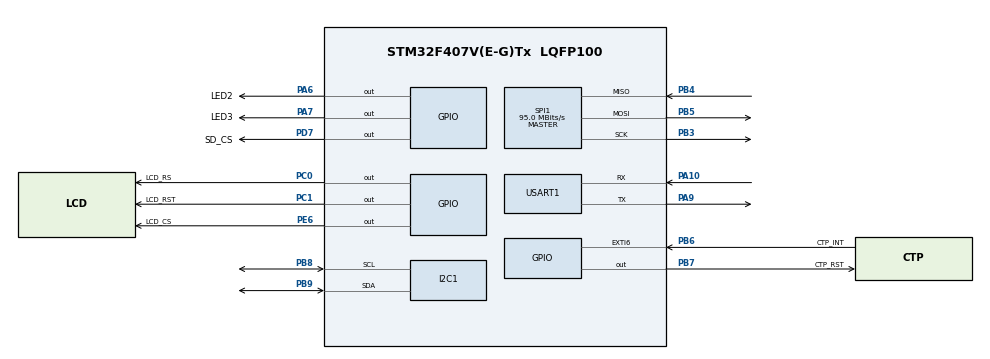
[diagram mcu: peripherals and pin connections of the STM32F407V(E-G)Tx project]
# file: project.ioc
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Dma.Request0=USART1_TX
Dma.Request1=SPI1_TX
Dma.Request2=SPI1_RX
Dma.SPI1_RX.2.Direction=DMA_PERIPH_TO_MEMORY
Dma.SPI1_RX.2.FIFOMode=DMA_FIFOMODE_DISABLE
Dma.SPI1_RX.2.Instance=DMA2_Stream0
Dma.SPI1_RX.2.MemDataAlignment=DMA_MDATAALIGN_BYTE
Dma.SPI1_RX.2.MemInc=DMA_MINC_ENABLE
Dma.SPI1_RX.2.Mode=DMA_NORMAL
Dma.SPI1_RX.2.PeriphDataAlignment=DMA_PDATAALIGN_BYTE
Dma.SPI1_RX.2.PeriphInc=DMA_PINC_DISABLE
Dma.SPI1_RX.2.Priority=DMA_PRIORITY_MEDIUM
Dma.SPI1_TX.1.Direction=DMA_MEMORY_TO_PERIPH
Dma.SPI1_TX.1.FIFOMode=DMA_FIFOMODE_DISABLE
Dma.SPI1_TX.1.Instance=DMA2_Stream3
Dma.SPI1_TX.1.MemDataAlignment=DMA_MDATAALIGN_BYTE
Dma.SPI1_TX.1.MemInc=DMA_MINC_ENABLE
Dma.SPI1_TX.1.Mode=DMA_NORMAL
Dma.SPI1_TX.1.PeriphDataAlignment=DMA_PDATAALIGN_BYTE
Dma.SPI1_TX.1.PeriphInc=DMA_PINC_DISABLE
Dma.SPI1_TX.1.Priority=DMA_PRIORITY_MEDIUM
Dma.USART1_TX.0.Direction=DMA_MEMORY_TO_PERIPH
Dma.USART1_TX.0.FIFOMode=DMA_FIFOMODE_DISABLE
Dma.USART1_TX.0.Instance=DMA2_Stream7
Dma.USART1_TX.0.MemDataAlignment=DMA_MDATAALIGN_BYTE
Dma.USART1_TX.0.MemInc=DMA_MINC_ENABLE
Dma.USART1_TX.0.Mode=DMA_NORMAL
Dma.USART1_TX.0.PeriphDataAlignment=DMA_PDATAALIGN_BYTE
Dma.USART1_TX.0.PeriphInc=DMA_PINC_DISABLE
Dma.USART1_TX.0.Priority=DMA_PRIORITY_MEDIUM
FREERTOS.Tasks01=defaultTask,0,128,StartDefaultTask,Default,NULL,Dynamic,NULL,NULL;BlinkLED2,-1,128,BlinkLED2_Task,Default,NULL,Dynamic,NULL,NULL;LVGL_TaskHandle,0,2304,LVGL_TaskHandler_Task,Default,NULL,Dynamic,NULL,NULL;FT6336_ScanTask,1,128,FT6336_Scan_Task,Default,NULL,Dynamic,NULL,NULL
FREERTOS.configENABLE_FPU=1
FREERTOS.configUSE_NEWLIB_REENTRANT=0
I2C1.I2C_Mode=I2C_Fast
Mcu.Family=STM32F4
Mcu.Name=STM32F407V(E-G)Tx
Mcu.Package=LQFP100
NVIC.DMA2_Stream0_IRQn=true\:5\:0\:true\:false\:true\:true\:false\:true\:true
NVIC.DMA2_Stream3_IRQn=true\:5\:0\:true\:false\:true\:true\:false\:true\:true
NVIC.DMA2_Stream7_IRQn=true\:5\:0\:true\:false\:true\:true\:false\:true\:true
NVIC.EXTI9_5_IRQn=true\:5\:0\:true\:false\:true\:true\:true\:true\:true
NVIC.PriorityGroup=NVIC_PRIORITYGROUP_4
NVIC.SPI1_IRQn=true\:3\:0\:true\:false\:true\:false\:true\:true\:true
NVIC.TIM1_BRK_TIM9_IRQn=true\:15\:0\:false\:false\:true\:false\:false\:true\:true
NVIC.TIM3_IRQn=true\:5\:0\:true\:false\:true\:true\:true\:true\:true
NVIC.TimeBase=TIM1_BRK_TIM9_IRQn
NVIC.TimeBaseIP=TIM9
NVIC.USART1_IRQn=true\:6\:0\:true\:false\:true\:true\:false\:true\:true
PA10.Mode=Asynchronous
PA10.Signal=USART1_RX
PA13.Mode=Serial_Wire
PA13.Signal=SYS_JTMS-SWDIO
PA14.Mode=Serial_Wire
PA14.Signal=SYS_JTCK-SWCLK
PA6.GPIO_Label=LED2
PA6.GPIO_Speed=GPIO_SPEED_FREQ_HIGH
PA6.PinState=GPIO_PIN_SET
PA6.Signal=GPIO_Output
PA7.GPIO_Label=LED3
PA7.GPIO_Speed=GPIO_SPEED_FREQ_HIGH
PA7.PinState=GPIO_PIN_SET
PA7.Signal=GPIO_Output
PA9.Mode=Asynchronous
PA9.Signal=USART1_TX
PB3.GPIO_PuPd=GPIO_PULLUP
PB3.Mode=Full_Duplex_Master
PB3.Signal=SPI1_SCK
PB4.GPIO_PuPd=GPIO_PULLUP
PB4.Mode=Full_Duplex_Master
PB4.Signal=SPI1_MISO
PB5.GPIO_PuPd=GPIO_PULLUP
PB5.Mode=Full_Duplex_Master
PB5.Signal=SPI1_MOSI
PB6.GPIO_Label=CTP_INT
PB6.GPIO_ModeDefaultEXTI=GPIO_MODE_IT_FALLING
PB6.GPIO_PuPd=GPIO_PULLUP
PB6.Signal=GPXTI6
PB7.GPIO_Label=CTP_RST
PB7.GPIO_Speed=GPIO_SPEED_FREQ_VERY_HIGH
PB7.PinState=GPIO_PIN_SET
PB7.Signal=GPIO_Output
PB8.GPIO_Pu=GPIO_PULLUP
PB8.Mode=I2C
PB8.Signal=I2C1_SCL
PB9.GPIO_Pu=GPIO_PULLUP
PB9.Mode=I2C
PB9.Signal=I2C1_SDA
PC0.GPIO_Label=LCD_RS
PC0.GPIO_ModeDefaultOutputPP=GPIO_MODE_OUTPUT_PP
PC0.GPIO_Speed=GPIO_SPEED_FREQ_VERY_HIGH
PC0.PinState=GPIO_PIN_SET
PC0.Signal=GPIO_Output
PC1.GPIO_Label=LCD_RST
PC1.GPIO_Speed=GPIO_SPEED_FREQ_VERY_HIGH
PC1.PinState=GPIO_PIN_SET
PC1.Signal=GPIO_Output
PC14-OSC32_IN.Mode=LSE-External-Oscillator
PC14-OSC32_IN.Signal=RCC_OSC32_IN
PC15-OSC32_OUT.Mode=LSE-External-Oscillator
PC15-OSC32_OUT.Signal=RCC_OSC32_OUT
PD7.GPIO_Label=SD_CS
PD7.GPIO_ModeDefaultOutputPP=GPIO_MODE_OUTPUT_PP
PD7.GPIO_PuPd=GPIO_PULLUP
PD7.GPIO_Speed=GPIO_SPEED_FREQ_VERY_HIGH
PD7.PinState=GPIO_PIN_SET
PD7.Signal=GPIO_Output
PE6.GPIO_Label=LCD_CS
PE6.GPIO_Speed=GPIO_SPEED_FREQ_VERY_HIGH
PE6.PinState=GPIO_PIN_SET
PE6.Signal=GPIO_Output
PH0-OSC_IN.Mode=HSE-External-Oscillator
PH0-OSC_IN.Signal=RCC_OSC_IN
PH1-OSC_OUT.Mode=HSE-External-Oscillator
PH1-OSC_OUT.Signal=RCC_OSC_OUT
ProjectManager.HeapSize=0x3500
ProjectManager.StackSize=0x1000
ProjectManager.TargetToolchain=MDK-ARM V5.32
RCC.48MHZClocksFreq_Value=95000000
RCC.AHBFreq_Value=190000000
RCC.APB1CLKDivider=RCC_HCLK_DIV4
RCC.APB1Freq_Value=47500000
RCC.APB1TimFreq_Value=95000000
RCC.APB2Freq_Value=190000000
RCC.APB2TimFreq_Value=190000000
RCC.CortexFreq_Value=190000000
RCC.HCLKFreq_Value=190000000
RCC.HSE_VALUE=8000000
RCC.HSI_VALUE=16000000
RCC.PLLM=4
RCC.PLLN=190
RCC.PLLSourceVirtual=RCC_PLLSOURCE_HSE
RCC.SYSCLKFreq_VALUE=190000000
RCC.SYSCLKSource=RCC_SYSCLKSOURCE_PLLCLK
RCC.VCOOutputFreq_Value=380000000
SPI1.BaudRatePrescaler=SPI_BAUDRATEPRESCALER_2
SPI1.CLKPhase=SPI_PHASE_2EDGE
SPI1.CLKPolarity=SPI_POLARITY_HIGH
SPI1.CalculateBaudRate=95.0 MBits/s
SPI1.Direction=SPI_DIRECTION_2LINES
SPI1.Mode=SPI_MODE_MASTER
SPI1.VirtualType=VM_MASTER
TIM3.AutoReloadPreload=TIM_AUTORELOAD_PRELOAD_ENABLE
TIM3.Period=1000-1
TIM3.Prescaler=90-1
USART1.VirtualMode=VM_ASYNC
VP_CRC_VS_CRC.Mode=CRC_Activate
VP_FREERTOS_VS_CMSIS_V1.Mode=CMSIS_V1
VP_SYS_VS_tim9.Mode=TIM9
VP_TIM3_VS_ClockSourceINT.Mode=Internal
board=custom

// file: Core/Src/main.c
/* USER CODE BEGIN Header */
/**
 ******************************************************************************
 * @file    : main.c
 * @brief   : Main program body
 * @author  : Zeruns
 * @brief   : 基于STM32F407的LVGL工程模板（MSP3526屏幕）,FreeRTOS版
 * @version : 0.2
 * @date    : 2024-05-27
 * @作者个人博客  : https://blog.zeruns.tech
 * @B站空间       : https://space.bilibili.com/8320520
 ******************************************************************************
 * @attention
 *
 * Copyright (c) 2024 STMicroelectronics.
 * All rights reserved.
 *
 * This software is licensed under terms that can be found in the LICENSE file
 * in the root directory of this software component.
 * If no LICENSE file comes with this software, it is provided AS-IS.
 *
 ******************************************************************************
 *    硬件接线：
 *    LCD            MCU/开发板         功能描述
 * ----------------------------------------------------------------------------
 *    GND       ->      GND     ->    LCD屏电源地
 *    VCC       ->      5V      ->    LCD屏电源正极
 *    LCD_CS    ->      PE6     ->    LCD屏SPI片选
 *    LCD_RST   ->      PC1     ->    LCD屏复位
 *    LCD_RS    ->      PC0     ->    LCD屏命令/数据选择
 *    SDI(MOSI) ->      PB5     ->    LCD屏SPI数据线，主机输出从机输入
 *    SCK       ->      PB3     ->    LCD屏SPI时钟线
 *    LED       ->      3.3V（可以自己接IO口，用软件控制背光）
 *    SDO(MISO) ->      PB4     ->    LCD屏SPI数据线，主机输入从机输出
 *    CTP_SCL   ->      PB8     ->    电容触摸屏控制器I2C时钟线
 *    CTP_RST   ->      PB7     ->    电容触摸屏控制器复位
 *    CTP_SDA   ->      PB9     ->    电容触摸屏控制器I2C数据线
 *    CTP_INT   ->      PB6     ->    电容触摸屏控制器中断信号
 ******************************************************************************
 */
/* USER CODE END Header */
#include "main.h"
#include "cmsis_os.h"
#include "crc.h"
#include "dma.h"
#include "i2c.h"
#include "spi.h"
#include "tim.h"
#include "usart.h"
#include "gpio.h"

/* USER CODE BEGIN Includes */
#include "LCD.h"
#include "lvgl.h"
#include "lv_port_disp.h"
#include "lv_port_indev.h"
#include "lv_demos.h"
#include "touch.h"
#include "FT6336.h"
/* USER CODE END Includes */

void SystemClock_Config(void);
void MX_FREERTOS_Init(void);

int main(void)
{

  /* MCU Configuration--------------------------------------------------------*/

  /* Reset of all peripherals, Initializes the Flash interface and the Systick. */
  HAL_Init();

  /* Configure the system clock */
  SystemClock_Config();

  /* Initialize all configured peripherals */
  MX_GPIO_Init();
  MX_DMA_Init();
  MX_USART1_UART_Init();
  MX_I2C1_Init();
  MX_TIM3_Init();
  MX_CRC_Init();
  MX_SPI1_Init();
  /* USER CODE BEGIN 2 */
  HAL_TIM_Base_Start_IT(&htim3); // 启动定时器3和定时器中断，1Hz

  /* USER CODE END 2 */

  /* Call init function for freertos objects (in cmsis_os2.c) */
  MX_FREERTOS_Init();

  /* Start scheduler */
  osKernelStart();

  /* We should never get here as control is now taken by the scheduler */

  /* Infinite loop */
  /* USER CODE BEGIN WHILE */

  //while (1)
  //{
    /* USER CODE END WHILE */

    /* USER CODE BEGIN 3 */
  //}
  /* USER CODE END 3 */
}

void SystemClock_Config(void)
{
  RCC_OscInitTypeDef RCC_OscInitStruct = {0};
  RCC_ClkInitTypeDef RCC_ClkInitStruct = {0};

  /** Configure the main internal regulator output voltage
  */
  __HAL_RCC_PWR_CLK_ENABLE();
  __HAL_PWR_VOLTAGESCALING_CONFIG(PWR_REGULATOR_VOLTAGE_SCALE1);

  /** Initializes the RCC Oscillators according to the specified parameters
  * in the RCC_OscInitTypeDef structure.
  */
  RCC_OscInitStruct.OscillatorType = RCC_OSCILLATORTYPE_HSE;
  RCC_OscInitStruct.HSEState = RCC_HSE_ON;
  RCC_OscInitStruct.PLL.PLLState = RCC_PLL_ON;
  RCC_OscInitStruct.PLL.PLLSource = RCC_PLLSOURCE_HSE;
  RCC_OscInitStruct.PLL.PLLM = 4;
  RCC_OscInitStruct.PLL.PLLN = 180;
  RCC_OscInitStruct.PLL.PLLP = RCC_PLLP_DIV2;
  RCC_OscInitStruct.PLL.PLLQ = 4;
  if (HAL_RCC_OscConfig(&RCC_OscInitStruct) != HAL_OK)
  {
    Error_Handler();
  }

  /** Initializes the CPU, AHB and APB buses clocks
  */
  RCC_ClkInitStruct.ClockType = RCC_CLOCKTYPE_HCLK|RCC_CLOCKTYPE_SYSCLK
                              |RCC_CLOCKTYPE_PCLK1|RCC_CLOCKTYPE_PCLK2;
  RCC_ClkInitStruct.SYSCLKSource = RCC_SYSCLKSOURCE_PLLCLK;
  RCC_ClkInitStruct.AHBCLKDivider = RCC_SYSCLK_DIV1;
  RCC_ClkInitStruct.APB1CLKDivider = RCC_HCLK_DIV4;
  RCC_ClkInitStruct.APB2CLKDivider = RCC_HCLK_DIV1;

  if (HAL_RCC_ClockConfig(&RCC_ClkInitStruct, FLASH_LATENCY_5) != HAL_OK)
  {
    Error_Handler();
  }
}

void HAL_TIM_PeriodElapsedCallback(TIM_HandleTypeDef *htim)
{
  if (htim->Instance == TIM9) {
    HAL_IncTick();
  }
  /* USER CODE BEGIN Callback 1 */
	if (htim->Instance == TIM3) // 定时器TIM3，中断时间1ms
  {
    //lv_tick_inc(1); // LVGL时基
  }
  /* USER CODE END Callback 1 */
}

void Error_Handler(void)
{
  __disable_irq();
  while (1)
  {
  }
}

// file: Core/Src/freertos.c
/* USER CODE BEGIN Header */
/**
 ******************************************************************************
 * File Name          : freertos.c
 * Description        : Code for freertos applications
 * @author  : Zeruns
 * @brief   : 基于STM32F407的LVGL工程模板（MSP3526屏幕）,FreeRTOS版
 * @version : 0.2
 * @date    : 2024-05-27
 * @作者个人博客  : https://blog.zeruns.tech
 * @B站空间       : https://space.bilibili.com/8320520
 ******************************************************************************
 * @attention
 *
 * Copyright (c) 2024 STMicroelectronics.
 * All rights reserved.
 *
 * This software is licensed under terms that can be found in the LICENSE file
 * in the root directory of this software component.
 * If no LICENSE file comes with this software, it is provided AS-IS.
 *
 ******************************************************************************
 *    硬件接线：
 *    LCD            MCU/开发板         功能描述
 * ----------------------------------------------------------------------------
 *    GND       ->      GND     ->    LCD屏电源地
 *    VCC       ->      5V      ->    LCD屏电源正极
 *    LCD_CS    ->      PE6     ->    LCD屏SPI片选
 *    LCD_RST   ->      PC1     ->    LCD屏复位
 *    LCD_RS    ->      PC0     ->    LCD屏命令/数据选择
 *    SDI(MOSI) ->      PB5     ->    LCD屏SPI数据线，主机输出从机输入
 *    SCK       ->      PB3     ->    LCD屏SPI时钟线
 *    LED       ->      3.3V（可以自己接IO口，用软件控制背光）
 *    SDO(MISO) ->      PB4     ->    LCD屏SPI数据线，主机输入从机输出
 *    CTP_SCL   ->      PB8     ->    电容触摸屏控制器I2C时钟线
 *    CTP_RST   ->      PB7     ->    电容触摸屏控制器复位
 *    CTP_SDA   ->      PB9     ->    电容触摸屏控制器I2C数据线
 *    CTP_INT   ->      PB6     ->    电容触摸屏控制器中断信号
 ******************************************************************************
 */
/* USER CODE END Header */

#include "FreeRTOS.h"
#include "task.h"
#include "main.h"
#include "cmsis_os.h"

/* USER CODE BEGIN Includes */
#include "usart.h"
#include "gpio.h"
#include "LCD.h"
#include "touch.h"
#include "lvgl.h"
#include "lv_port_disp.h"
#include "lv_port_indev.h"
#include "lv_demos.h"
/* USER CODE END Includes */

/* USER CODE BEGIN Variables */
osSemaphoreId SPI1_Send_OK; // 定义信号量，用于SPI1发送完成标志
uint8_t CTP_INT_Flag;       // 触摸屏中断标志位
/* USER CODE END Variables */
osThreadId defaultTaskHandle;
osThreadId BlinkLED2Handle;
osThreadId LVGL_TaskHandleHandle;
osThreadId FT6336_ScanTaskHandle;

void StartDefaultTask(void const *argument);
void BlinkLED2_Task(void const *argument);
void LVGL_TaskHandler_Task(void const *argument);
void FT6336_Scan_Task(void const *argument);

void MX_FREERTOS_Init(void); /* (MISRA C 2004 rule 8.1) */

/* GetIdleTaskMemory prototype (linked to static allocation support) */
void vApplicationGetIdleTaskMemory(StaticTask_t **ppxIdleTaskTCBBuffer, StackType_t **ppxIdleTaskStackBuffer, uint32_t *pulIdleTaskStackSize);

/* USER CODE BEGIN GET_IDLE_TASK_MEMORY */
static StaticTask_t xIdleTaskTCBBuffer;
static StackType_t xIdleStack[configMINIMAL_STACK_SIZE];

void vApplicationGetIdleTaskMemory(StaticTask_t **ppxIdleTaskTCBBuffer, StackType_t **ppxIdleTaskStackBuffer, uint32_t *pulIdleTaskStackSize)
{
  *ppxIdleTaskTCBBuffer = &xIdleTaskTCBBuffer;
  *ppxIdleTaskStackBuffer = &xIdleStack[0];
  *pulIdleTaskStackSize = configMINIMAL_STACK_SIZE;
  /* place for user code */
}
/* USER CODE END GET_IDLE_TASK_MEMORY */

void MX_FREERTOS_Init(void)
{

  /* USER CODE BEGIN RTOS_SEMAPHORES */
  /* add semaphores, ... */
  osSemaphoreDef(SPI1_Send_OK);                                   // 定义一个名为SPI1_Send_OK的信号量
  SPI1_Send_OK = osSemaphoreCreate(osSemaphore(SPI1_Send_OK), 1); // 创建名为SPI1_Send_OK的信号量实例，并初始化为1。

  /* USER CODE END RTOS_SEMAPHORES */

  /* Create the thread(s) */
  /* definition and creation of defaultTask */
  osThreadDef(defaultTask, StartDefaultTask, osPriorityNormal, 0, 128);
  defaultTaskHandle = osThreadCreate(osThread(defaultTask), NULL);

  /* definition and creation of BlinkLED2 */
  osThreadDef(BlinkLED2, BlinkLED2_Task, osPriorityBelowNormal, 0, 128);
  BlinkLED2Handle = osThreadCreate(osThread(BlinkLED2), NULL);

  /* definition and creation of LVGL_TaskHandle */
  osThreadDef(LVGL_TaskHandle, LVGL_TaskHandler_Task, osPriorityNormal, 0, 2304);
  LVGL_TaskHandleHandle = osThreadCreate(osThread(LVGL_TaskHandle), NULL);

  /* definition and creation of FT6336_ScanTask */
  osThreadDef(FT6336_ScanTask, FT6336_Scan_Task, osPriorityAboveNormal, 0, 128);
  FT6336_ScanTaskHandle = osThreadCreate(osThread(FT6336_ScanTask), NULL);

}

void StartDefaultTask(void const *argument)
{
  /* USER CODE BEGIN StartDefaultTask */
  USART1_Printf("%d : Run StartDefaultTask\r\n", osKernelSysTick());
  /* Infinite loop */
  for (;;)
  {
    osDelay(100);
  }
  /* USER CODE END StartDefaultTask */
}

/* USER CODE BEGIN Header_BlinkLED2_Task */
/**
 * @brief BlinkLED2线程，用于LED2闪烁.
 * @param argument: Not used
 * @note LED2闪烁
 * @retval None
 */
/* USER CODE END Header_BlinkLED2_Task */
void BlinkLED2_Task(void const *argument)
{
  /* USER CODE BEGIN BlinkLED2_Task */
  USART1_Printf("%d : Run BlinkLED2_Task\r\n", osKernelSysTick());
  /* Infinite loop */
  for (;;)
  {
    HAL_GPIO_TogglePin(LED2_GPIO_Port, LED2_Pin); // LED2电平翻转
    osDelay(500);
  }
  /* USER CODE END BlinkLED2_Task */
}

void LVGL_TaskHandler_Task(void const *argument)
{
  /* USER CODE BEGIN LVGL_TaskHandler_Task */
  USART1_Printf("%d : Run LVGL_TaskHandler_Task\r\n", osKernelSysTick());
  lv_init(); // LVGL初始化
  USART1_Printf("%d : lv_init() Finish\r\n", osKernelSysTick());
  lv_port_disp_init(); // LVGL显示初始化
  USART1_Printf("%d : lv_port_disp_init() Finish\r\n", osKernelSysTick());
  LCD_Switch_Dir(0); // 旋转屏幕方向
  USART1_Printf("%d : LCD_Switch_Dir(0) Finish\r\n", osKernelSysTick());

  // LVGL自带示例程序
  lv_demo_widgets();
  //  lv_demo_stress();
  //  lv_demo_benchmark();
  //  lv_demo_music();

  USART1_Printf("%d : LCD ID:%d\r\n", osKernelSysTick(), LCD_Read_ID());

  /* Infinite loop */
  for (;;)
  {
    lv_task_handler(); // LVGL任务处理
    osDelay(5);        // 延时5ms
  }
  /* USER CODE END LVGL_TaskHandler_Task */
}

void FT6336_Scan_Task(void const *argument)
{
  /* USER CODE BEGIN FT6336_Scan_Task */
  lv_port_indev_init(); // LVGL输入设备初始化
  USART1_Printf("%d : lv_port_indev_init() Finish\r\n", osKernelSysTick());
  /* Infinite loop */
  for (;;)
  {
    if (CTP_INT_Flag == 1)
    {
      tp_dev.scan(); // 扫描触摸点
      CTP_INT_Flag = 0;
    }
    osDelay(10);
  }
  /* USER CODE END FT6336_Scan_Task */
}
